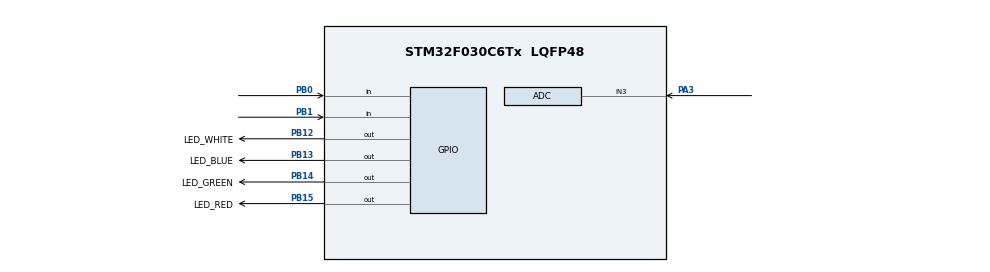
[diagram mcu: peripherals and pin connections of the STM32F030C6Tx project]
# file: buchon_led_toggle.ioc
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Mcu.Family=STM32F0
Mcu.Name=STM32F030C6Tx
Mcu.Package=LQFP48
PA13.Mode=Serial_Wire
PA13.Signal=SYS_SWDIO
PA14.Mode=Serial_Wire
PA14.Signal=SYS_SWCLK
PA3.Mode=IN3
PA3.Signal=ADC_IN3
PB0.Signal=GPIO_Input
PB1.Signal=GPIO_Input
PB12.GPIO_Label=LED_WHITE
PB12.Signal=GPIO_Output
PB13.GPIO_Label=LED_BLUE
PB13.Signal=GPIO_Output
PB14.GPIO_Label=LED_GREEN
PB14.Signal=GPIO_Output
PB15.GPIO_Label=LED_RED
PB15.Signal=GPIO_Output
PC14-OSC32_IN.Mode=LSE-External-Oscillator
PC14-OSC32_IN.Signal=RCC_OSC32_IN
PC15-OSC32_OUT.Mode=LSE-External-Oscillator
PC15-OSC32_OUT.Signal=RCC_OSC32_OUT
ProjectManager.HeapSize=0x200
ProjectManager.StackSize=0x400
ProjectManager.TargetToolchain=EWARM V8.32
RCC.AHBFreq_Value=48000000
RCC.APB1Freq_Value=48000000
RCC.APB1TimFreq_Value=48000000
RCC.HCLKFreq_Value=48000000
RCC.PLLMUL=RCC_PLL_MUL12
RCC.RTCClockSelection=RCC_RTCCLKSOURCE_LSE
RCC.SYSCLKFreq_VALUE=48000000
RCC.SYSCLKSource=RCC_SYSCLKSOURCE_PLLCLK
VP_RTC_VS_RTC_Activate.Mode=RTC_Enabled
VP_RTC_VS_RTC_Calendar.Mode=RTC_Calendar
board=custom

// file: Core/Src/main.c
/* USER CODE BEGIN Header */
/**
  ******************************************************************************
  * @file           : main.c
  * @brief          : Main program body
  ******************************************************************************
  * @attention
  *
  * <h2><center>&copy; Copyright (c) 2022 STMicroelectronics.
  * All rights reserved.</center></h2>
  *
  * This software component is licensed by ST under BSD 3-Clause license,
  * the "License"; You may not use this file except in compliance with the
  * License. You may obtain a copy of the License at:
  *                        opensource.org/licenses/BSD-3-Clause
  *
  ******************************************************************************
  */
/* USER CODE END Header */
#include "main.h"
#include "adc.h"
#include "rtc.h"
#include "gpio.h"

/* USER CODE BEGIN Includes */
#include <string.h>
#include <math.h>

/* USER CODE END Includes */

/* USER CODE BEGIN PV */
LED_T m_red;
LED_T m_green;
LED_T m_blue;
LED_T m_white;

extern RTC_HandleTypeDef hrtc;

/* USER CODE END PV */

void SystemClock_Config(void);

/* USER CODE BEGIN 0 */
uint32_t tr = 0;
uint32_t tr_cnt = 0;
uint8_t g_step = STEP1;
uint8_t b_w_step = STEP1;

/* USER CODE END 0 */

int main(void)////----
{

  /* MCU Configuration--------------------------------------------------------*/

  /* Reset of all peripherals, Initializes the Flash interface and the Systick. */
  HAL_Init();

  /* Configure the system clock */
  SystemClock_Config();

  /* Initialize all configured peripherals */
  MX_GPIO_Init();
  MX_ADC_Init();
  MX_RTC_Init();
  /* USER CODE BEGIN 2 */
  HAL_Delay(100);
  HAL_RTCEx_SetSmoothCalib(&hrtc,0,0,0x036); //54

  /* USER CODE END 2 */

  /* Infinite loop */
  while (1)
  {

    /* USER CODE BEGIN 3 */

    if(RTC->TR != tr)
	{
		tr = RTC->TR;
		tr_cnt ++;

	}
    switch(m_red.step)
 	{
		case STEP1:
			RED_ON;
			m_red.past_time = Get_Now_RTC_time();
			m_red.step = STEP2;
		break;

		case STEP2:
			Green_config();
			Blue_White_config();

		    if(Get_Now_RTC_time() >= m_red.past_time + RED_ON_TIME)
	 		{
				Init_All_Led();
				m_red.past_time = Get_Now_RTC_time();
				m_red.step = STEP3;
	 		}
		break;

		case STEP3:
			if(Get_Now_RTC_time() >= m_red.past_time + RED_OFF_TIME)
	 		{
				m_red.step = STEP1;
	 		}
		break;
 	}

  }
  /* USER CODE END 3 */
}

void SystemClock_Config(void)
{
  RCC_OscInitTypeDef RCC_OscInitStruct = {0};
  RCC_ClkInitTypeDef RCC_ClkInitStruct = {0};
  RCC_PeriphCLKInitTypeDef PeriphClkInit = {0};

  /** Configure LSE Drive Capability
  */
  HAL_PWR_EnableBkUpAccess();
  __HAL_RCC_LSEDRIVE_CONFIG(RCC_LSEDRIVE_HIGH);
  /** Initializes the RCC Oscillators according to the specified parameters
  * in the RCC_OscInitTypeDef structure.
  */
  RCC_OscInitStruct.OscillatorType = RCC_OSCILLATORTYPE_HSI14|RCC_OSCILLATORTYPE_HSE
                              |RCC_OSCILLATORTYPE_LSE;
  RCC_OscInitStruct.HSEState = RCC_HSE_ON;
  RCC_OscInitStruct.LSEState = RCC_LSE_ON;
  RCC_OscInitStruct.HSI14State = RCC_HSI14_ON;
  RCC_OscInitStruct.HSI14CalibrationValue = 16;
  RCC_OscInitStruct.PLL.PLLState = RCC_PLL_ON;
  RCC_OscInitStruct.PLL.PLLSource = RCC_PLLSOURCE_HSE;
  RCC_OscInitStruct.PLL.PLLMUL = RCC_PLL_MUL3;
  RCC_OscInitStruct.PLL.PREDIV = RCC_PREDIV_DIV1;
  if (HAL_RCC_OscConfig(&RCC_OscInitStruct) != HAL_OK)
  {
    Error_Handler();
  }
  /** Initializes the CPU, AHB and APB buses clocks
  */
  RCC_ClkInitStruct.ClockType = RCC_CLOCKTYPE_HCLK|RCC_CLOCKTYPE_SYSCLK
                              |RCC_CLOCKTYPE_PCLK1;
  RCC_ClkInitStruct.SYSCLKSource = RCC_SYSCLKSOURCE_PLLCLK;
  RCC_ClkInitStruct.AHBCLKDivider = RCC_SYSCLK_DIV1;
  RCC_ClkInitStruct.APB1CLKDivider = RCC_HCLK_DIV1;

  if (HAL_RCC_ClockConfig(&RCC_ClkInitStruct, FLASH_LATENCY_1) != HAL_OK)
  {
    Error_Handler();
  }
  PeriphClkInit.PeriphClockSelection = RCC_PERIPHCLK_RTC;
  PeriphClkInit.RTCClockSelection = RCC_RTCCLKSOURCE_LSE;
  if (HAL_RCCEx_PeriphCLKConfig(&PeriphClkInit) != HAL_OK)
  {
    Error_Handler();
  }
}

/* USER CODE BEGIN 4 */
void Led_toggle_config(LED_T *led,uint32_t on_time, uint32_t off_time,uint16_t pin)
{
	TIME_T dest_time = {0,};

	RTC_TimeTypeDef RTC_times;
	switch(led->step)
	{
		case STEP1:
			HAL_GPIO_WritePin(LED_PORT, pin, GPIO_PIN_SET);
			led->step = STEP2;
			led->on_flag = ON;
			led->past_time = Get_Now_RTC_time();
		break;

		case STEP2:
			if(Get_Now_RTC_time() >= led->past_time + on_time )
	 		{
				led->step = STEP3;
	 		}
		break;

		case STEP3:
			HAL_GPIO_WritePin(LED_PORT, pin, GPIO_PIN_RESET);
			led->step = STEP4;
			led->on_flag = OFF;
			led->past_time = Get_Now_RTC_time();

		break;

		case STEP4:
			if(Get_Now_RTC_time() >= led->past_time + off_time )
	 		{
				led->step = STEP1;
	 		}
		break;
	}

}

void Led_toggle_config2(LED_T *led,uint32_t on_time, uint32_t off_time,uint16_t pin)
{
	//TIME_T dest_time = {0,};
	RTC_TimeTypeDef RTC_times={0,};

	switch(led->step)
	{
		case STEP1:
			HAL_GPIO_WritePin(LED_PORT, pin, GPIO_PIN_SET);
			led->step = STEP2;

			HAL_RTC_GetTime(&hrtc, &RTC_times,RTC_FORMAT_BIN);
			time_to_sec(&RTC_times,on_time, &led->dest_time);

		break;

		case STEP2:
			if(Get_time(led->dest_time, led))
	 		{
				led->step = STEP3;
	 		}
		break;

		case STEP3:
			HAL_GPIO_WritePin(LED_PORT, pin, GPIO_PIN_RESET);
			led->step = STEP4;

			HAL_RTC_GetTime(&hrtc, &RTC_times,RTC_FORMAT_BIN);
			time_to_sec(&RTC_times,off_time,&led->dest_time);
		break;

		case STEP4:
			if(Get_time(led->dest_time, led))
	 		{
				led->step = STEP1;
	 		}
		break;
	}

}

uint32_t temp = 0;
float Check_temperture()
{
	uint32_t adc_value;
	float Vin,R1 = 0;
	float a,b = 0;

	adc_value = Read_ADC();

	if(adc_value==0) return temp;

 	Vin = (adc_value / 4095.0) * 5.0;
 	R1 = Vin/(5.0 - Vin) * 10000.0;

	 if(R1 > 26250.0)
	 {
	   a = -20.0;
	   b = 208.47;
	 }
	 else if(R1 > 4025.0)
	 {
	   a = -26.6;
	   b = 270.54;
	 }
	 else
	 {
	   a = -36.18;
	   b = 349.45;
	 }

	 temp =a*log(R1) + b;

	 return temp;
}

void Green_config()
{
	uint32_t temper = 0;
	switch(g_step)
	{
		case STEP1:
			Led_toggle_config(&m_green, GREEN_ON_TIME, GREEN_OFF_TIME, LED_GREEN_Pin);

			temper = Check_temperture();
			if(temper >= TEMP_TH)
			{
				memset(&m_green,0,sizeof(LED_T));
				GREEN_ON;
				g_step = STEP2;
			}
		break;
		case STEP2:

			temper = Check_temperture();
			if(temper < TEMP_TH)
			{
				GREEN_OFF;
				g_step = STEP1;
			}
		break;

	}

}

void Blue_White_config()
{

	switch(b_w_step)
	{
		case STEP1:
			if(Check_button() == ON)
			{
				memset(&m_blue,0,sizeof(LED_T));
				BLUE_OFF;
				b_w_step = STEP2;
			}
			Led_toggle_config(&m_blue, BLUE_ON_TIME, BLUE_OFF_TIME, LED_BLUE_Pin);

		break;
		case STEP2:
			if(Check_button() == OFF)
			{
				memset(&m_white,0,sizeof(LED_T));
				WHITE_OFF;
				b_w_step = STEP1;
			}

		Led_toggle_config(&m_white, WHITE_ON_TIME, WHITE_OFF_TIME, LED_WHITE_Pin);
		break;

	}

}

uint8_t Check_button()
{
	GPIO_PinState button0,button1 = 0;

	button0 = HAL_GPIO_ReadPin(GPIOB, GPIO_PIN_0);
	button1 = HAL_GPIO_ReadPin(GPIOB, GPIO_PIN_1);

	if(button0 && button1)
	{
		return ON;
	}
	else
	{
		return OFF;
	}
}

uint8_t Init_All_Led()
{
	memset(&m_red,0,sizeof(LED_T));
	memset(&m_blue,0,sizeof(LED_T));
	memset(&m_green,0,sizeof(LED_T));
	memset(&m_white,0,sizeof(LED_T));

	RED_OFF;	GREEN_OFF;	BLUE_OFF;	WHITE_OFF;
	g_step = STEP1;
	b_w_step = STEP1;
}

uint32_t Get_Now_RTC_time()
{
	uint32_t time = 0;

	time = tr_cnt;
	return time;
}
RTC_TimeTypeDef times;

uint8_t Get_time(TIME_T dest, LED_T *led)
{
	RTC_TimeTypeDef time;

	if(HAL_GetTick() > led->past_time_small +10)
	{
		HAL_RTC_GetTime(&hrtc, &time,RTC_FORMAT_BIN);

		if(dest.hour == time.Hours && dest.min == time.Minutes && dest.sec == time.Seconds )
		{
			return SET;
		}
		led->past_time_small = HAL_GetTick();
	}

	return RESET;
}

uint32_t now_sec = 0;
void time_to_sec(RTC_TimeTypeDef* time, uint32_t wait_time,TIME_T *dest)
{

	TIME_T add;

	add.hour = wait_time/3600;
	add.min = (wait_time%3600)/60;
	add.sec = wait_time%60;

	dest->hour = time->Hours + add.hour;
	dest->min = time->Minutes +add.min;
	dest->sec = time->Seconds + add.sec;

	if(dest->sec >= 60)
	{
		dest->sec -= 60;
		dest->min++;
	}

	if(dest->min >= 60)
	{
		dest->min -= 60;
		dest->hour++;
	}

	if(dest->hour > 12)
	{
		dest->hour -= 12;
	}

}
void time_to_sec_config()
{
	TIME_T dest_time = {0,};

	HAL_RTC_GetTime(&hrtc, &times,RTC_FORMAT_BIN);
	HAL_Delay(10);
	time_to_sec(&times,5000,&dest_time);

}
/* USER CODE END 4 */

void Error_Handler(void)
{
  __disable_irq();
  while (1)
  {
  }
}

/************************ (C) COPYRIGHT STMicroelectronics *****END OF FILE****/
